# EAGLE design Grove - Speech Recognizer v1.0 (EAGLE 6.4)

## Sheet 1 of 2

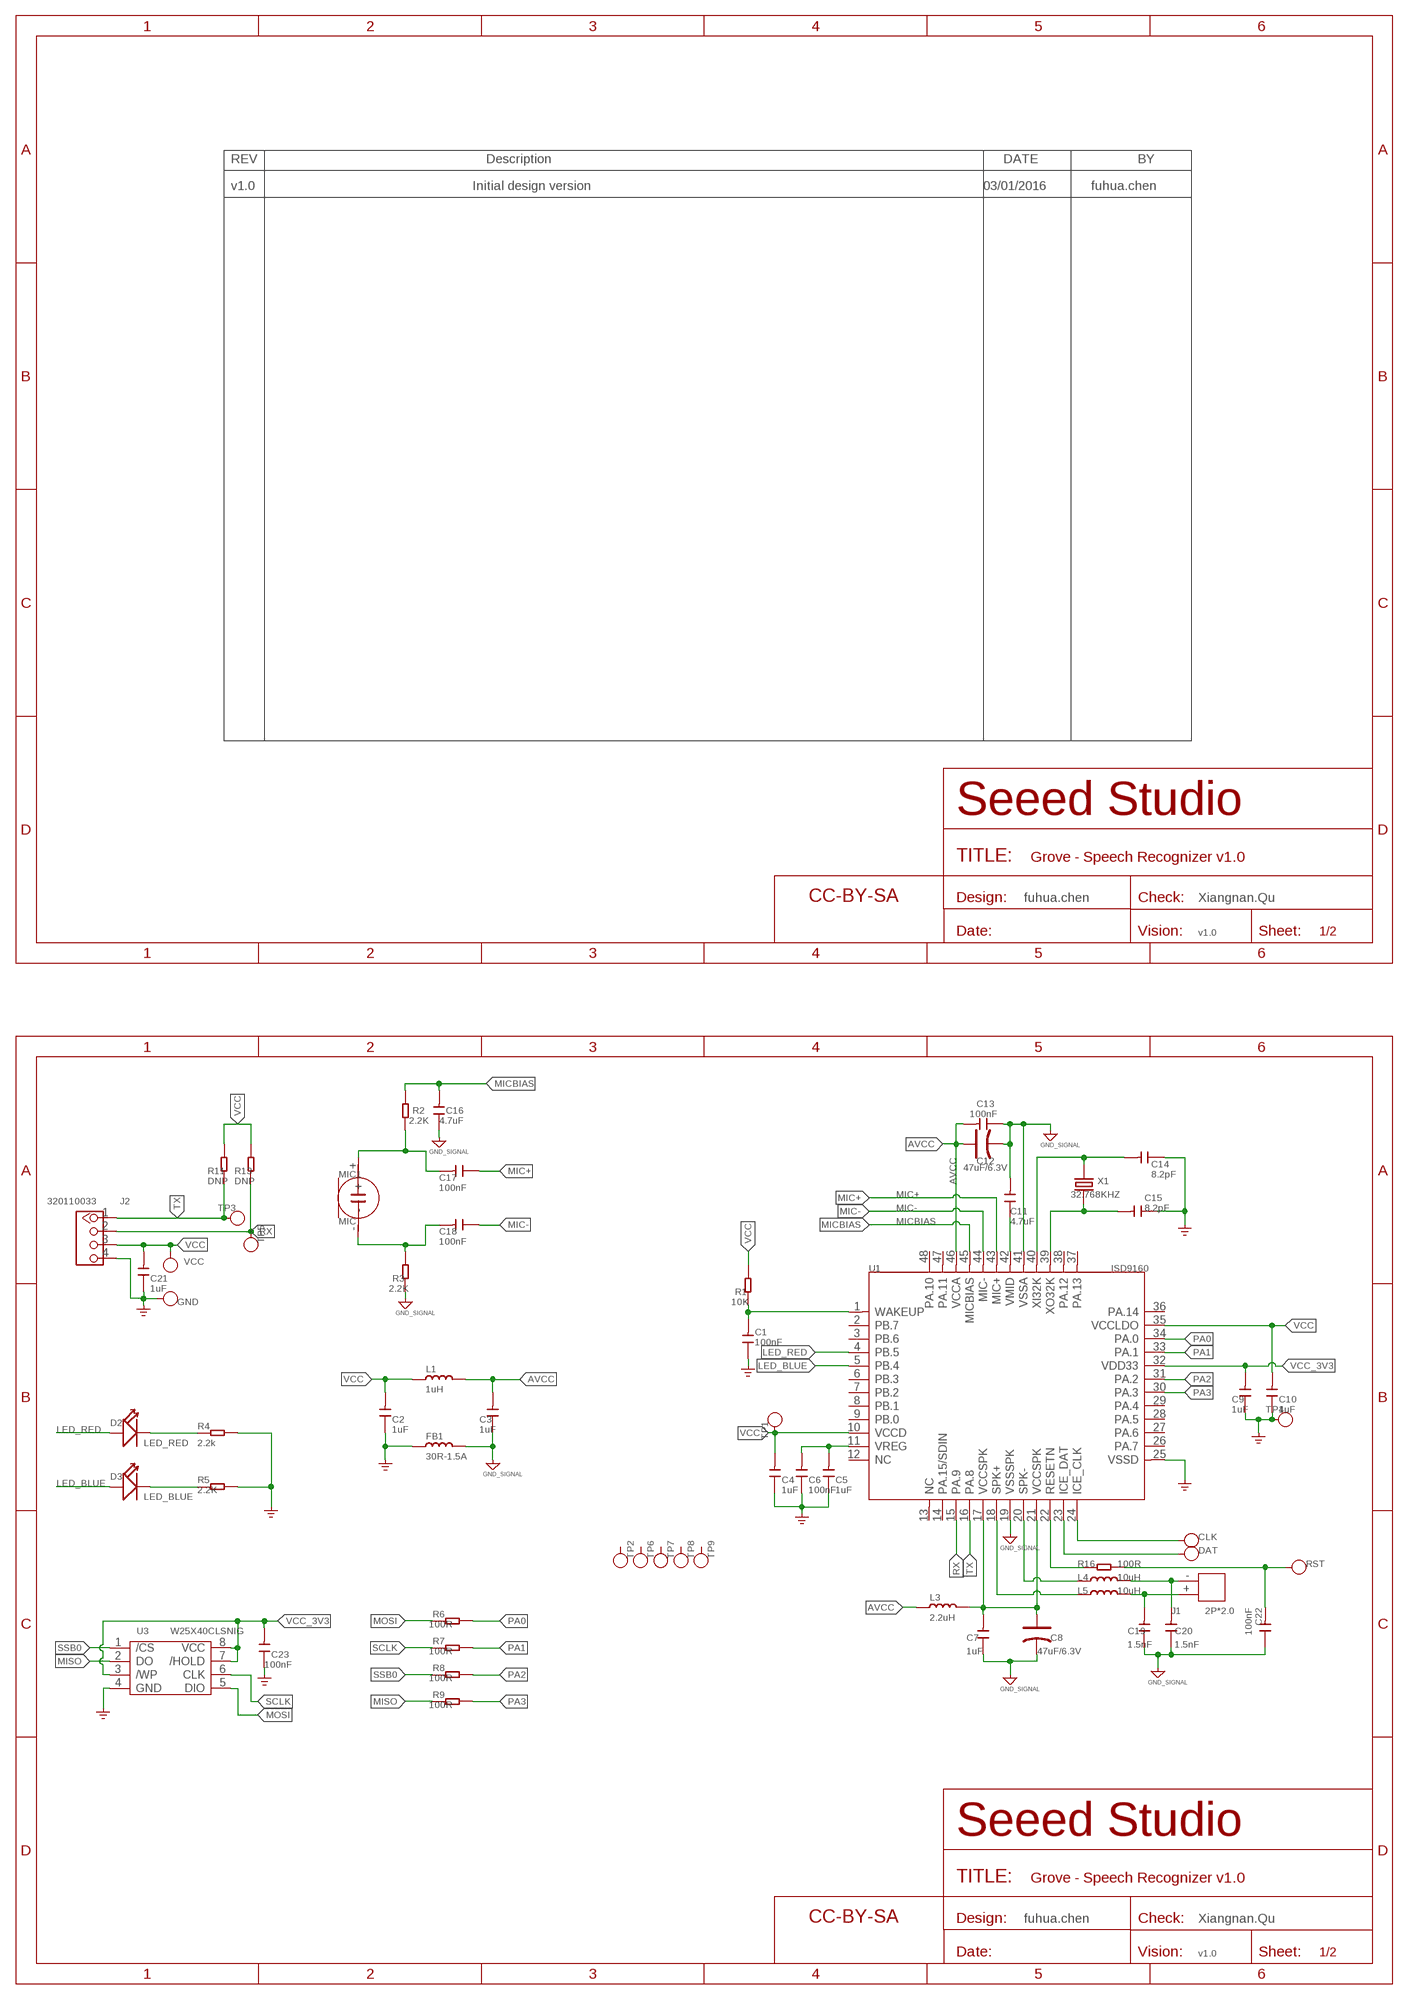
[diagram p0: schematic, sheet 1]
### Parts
C1  100nF  CAP-0402  [C0402]
C2  1uF  CAP-0402  [C0402]
C3  1uF  CAP-0402  [C0402]
C4  1uF  CAP-0402  [C0402]
C5  1uF  CAP-0402  [C0402]
C6  100nF  CAP-0402  [C0402]
C7  1uF  CAP-0402  [C0402]
C8  47uF/6.3V  CAP-POLAR-AVX-A  [AVX-A]
C9  1uF  CAP-0402  [C0402]
C10  1uF  CAP-0402  [C0402]
C11  4.7uF  CAP-0805  [C0805]
C12  47uF/6.3V  CAP-POLAR-AVX-A  [AVX-A]
C13  100nF  CAP-0402  [C0402]
C14  8.2pF  CAP-0402  [C0402]
C15  8.2pF  CAP-0402  [C0402]
C16  4.7uF  CAP-0805  [C0805]
C17  100nF  CAP-0402  [C0402]
C18  100nF  CAP-0402  [C0402]
C19  1.5nF  CAP-0402  [C0402]
C20  1.5nF  CAP-0402  [C0402]
C21  1uF  CAP-0402  [C0402]
C22  100nF  CAP-0402  [C0402]
C23  100nF  CAP-0402  [C0402]
CLK  DNP  TEST-POINT'4545'  [TP-D45MIL]
D2  LED_RED  LED-0402  [LED-0402]
D3  LED_BLUE  LED-0402  [LED-0402]
DAT  DNP  TEST-POINT'4545'  [TP-D45MIL]
FB1  30R-1.5A  INDUCTOR/FERRITE-BEAD'0603'  [L0603]
FR1  DNP  SEEEDSTUDIO-OPEN-SCH-FRAME  [SEEEDSTUDIO-PCB-FRAME]
FR2  DNP  SEEEDSTUDIO-OPEN-SCH-FRAME  [SEEEDSTUDIO-PCB-FRAME]
GND  DNP  TEST-POINT'4545'  [TP-D45MIL]
J1  2P*2.0  JST-2P-DIP'2.0'  [H2-2.0-6X4.5MM]
J2  320110033  GROVE-CONNECTOR-DIP-2.0  [HW4-2.0]
L1  1uH  INDUCTOR/FERRITE-BEAD'0805'  [L0805]
L3  2.2uH  INDUCTOR/FERRITE-BEAD'0805'  [L0805]
L4  10uH  INDUCTOR/FERRITE-BEAD'0805'  [L0805]
L5  10uH  INDUCTOR/FERRITE-BEAD'0805'  [L0805]
MIC1  MIC  MIC-2P'EAO-9745-PFA-C1033-28-008'  [MIC2-D9.7XH4.5MM]
R1  10K  RES-0402  [R0402]
R2  2.2K  RES-0402  [R0402]
R3  2.2K  RES-0402  [R0402]
R4  2.2k  RES-0402  [R0402]
R5  2.2K  RES-0402  [R0402]
R6  100R  RES-0402  [R0402]
R7  100R  RES-0402  [R0402]
R8  100R  RES-0402  [R0402]
R9  100R  RES-0402  [R0402]
R11  DNP  RES-0402  [R0402]
R13  DNP  RES-0402  [R0402]
R16  100R  RES-0402  [R0402]
RST  DNP  TEST-POINT'4545'  [TP-D45MIL]
TP1  TEST-POINT'4545'  [TP-D45MIL]
TP2  TEST-POINT'4545'  [TP-D45MIL]
TP3  TEST-POINT'4545'  [TP-D45MIL]
TP4  TEST-POINT'4545'  [TP-D45MIL]
TP5  TEST-POINT'4545'  [TP-D45MIL]
TP6  TEST-POINT'4545'  [TP-D45MIL]
TP7  TEST-POINT'4545'  [TP-D45MIL]
TP8  TEST-POINT'4545'  [TP-D45MIL]
TP9  TEST-POINT'4545'  [TP-D45MIL]
U1  ISD9160  MCU-ISD9160  [LQFP48-0.5-7X7MM]
U3  W25X40CLSNIG  FLASH-W25X80  [SOIC8-1.27-5.3X5.3MM]
VCC  DNP  TEST-POINT'4545'  [TP-D45MIL]
X1  32.768KHZ  CRYSTAL-2P-3215  [X2-SMD-3.2X1.5X0.55MM]

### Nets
AGND: C3.1 C7.1 C8.- C11.2 C12.- C13.1 C16.1 C19.1 C20.1 C22.1 FB1.2 R3.1 U1.19(VSSSPK) U1.41(VSSA) ; supply symbol labelled GND_SIGNAL
AVCC: C3.2 C12.+ C13.2 L1.2 L3.1 U1.46(VCCA)
GND: C1.1 C2.1 C4.1 C5.1 C6.1 C9.1 C10.1 C14.1 C15.1 C21.1 C23.1 FB1.1 GND.T J2.4 R4.1 R5.1 TP4.T U1.25(VSSD) U3.4(GND) ; supply symbol labelled GND_POWER
ICE_CLK: CLK.T U1.24(ICE_CLK)
LED_BLUE: D3.+ U1.5(PB.4)
LED_RED: D2.+ U1.4(PB.5)
MIC+: C17.1 U1.43(MIC+)
MIC-: C18.1 U1.44(MIC-)
MICBIAS: C16.2 R2.2 U1.45(MICBIAS)
MISO: R9.2 U3.2(DO)
MOSI: R6.2 U3.5(DIO)
N$1: C1.2 R1.1 U1.1(WAKEUP)
N$2: C7.2 C8.+ L3.2 U1.17(VCCSPK) U1.21(VCCSPK)
N$3: C5.2 C6.2 U1.11(VREG)
N$4: C11.1 U1.42(VMID)
N$5: C17.2 MIC1.+ R2.1
N$6: D2.- R4.2
N$7: C14.2 U1.40(XI32K) X1.1
N$8: C15.2 U1.39(XO32K) X1.2
N$9: C18.2 MIC1.- R3.2
N$10: D3.- R5.2
N$12: DAT.T U1.23(ICE_DAT)
N$13: L4.1 U1.20(SPK-)
N$15: C22.2 R16.1 RST.T
N$16: R16.2 U1.22(RESETN)
N$23: L5.1 U1.18(SPK+)
N$24: C20.2 J1.- L4.2
N$25: C19.2 J1.+ L5.2
PA0: R6.1 U1.34(PA.0)
PA1: R7.1 U1.33(PA.1)
PA2: R8.1 U1.31(PA.2)
PA3: R9.1 U1.30(PA.3)
RX: J2.2 R13.1 TP5.T U1.15(PA.9)
SCLK: R7.2 U3.6(CLK)
SSB0: R8.2 U3.1(/CS)
TX: J2.1 R11.1 TP3.T U1.16(PA.8)
VCC: C2.2 C4.2 C10.2 C21.2 J2.3 L1.1 R1.2 R11.2 R13.2 TP1.T U1.10(VCCD) U1.35(VCCLDO) VCC.T
VCC_3V3: C9.2 C23.2 U1.32(VDD33) U3.3(/WP) U3.7(/HOLD) U3.8(VCC)
Unconnected: TP2.T TP6.T TP7.T TP8.T TP9.T U1.2(PB.7) U1.3(PB.6) U1.6(PB.3) U1.7(PB.2) U1.8(PB.1) U1.9(PB.0) U1.12(NC) U1.13(NC) U1.14(PA.15/SDIN) U1.26(PA.7) U1.27(PA.6) U1.28(PA.5) U1.29(PA.4) U1.36(PA.14) U1.37(PA.13) U1.38(PA.12) U1.47(PA.11) U1.48(PA.10)

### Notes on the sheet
- v1.0 | Initial design version | 03/01/2016 | fuhua.chen
- fuhua.chen | Xiangnan.Qu
- v1.0
- fuhua.chen | Xiangnan.Qu
- v1.0

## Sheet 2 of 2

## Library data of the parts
C1-C7 C9-C11 C13-C23 = Discrete-new:CAP: Ceramic Capacitors
C8 C12 = Discrete-new:CAP-POLAR: Electrolytic Capacitors,Tantalum Capacitors and Super Capacitors
CLK DAT GND RST TP1-TP9 VCC = Discrete-new:TEST-POINT; PARTNO: DNP
D2 D3 = Discrete-new:LED
FB1 L1 L3-L5 = Discrete-new:INDUCTOR/FERRITE-BEAD
FR1 FR2 = moudle-new:SEEEDSTUDIO-OPEN-SCH-FRAME
J1 = Connector-new:JST-2P-DIP: 2P-2.0:320110049;2P-2.0-90D:320110027;2P-2.54:320110053;2P-2.54-90D:320110000
J2 = Connector-new:GROVE-CONNECTOR-DIP: 4P-2.0:320110033;4P-2.0-90D:320110034
MIC1 = Discrete-new:MIC-2P: 312030029
R1-R9 R11 R13 R16 = Discrete-new:RES
U1 = template:MCU-ISD9160
U3 = IC-new:FLASH-W25X80: 1M-BIT,2M-BIT,4M-BIT AND 8M-BIT SERIAL FLASH MEMORY WITH 4KB SECTORS AND DUAL OUTPUT SPI
X1 = Discrete-new:CRYSTAL-2P

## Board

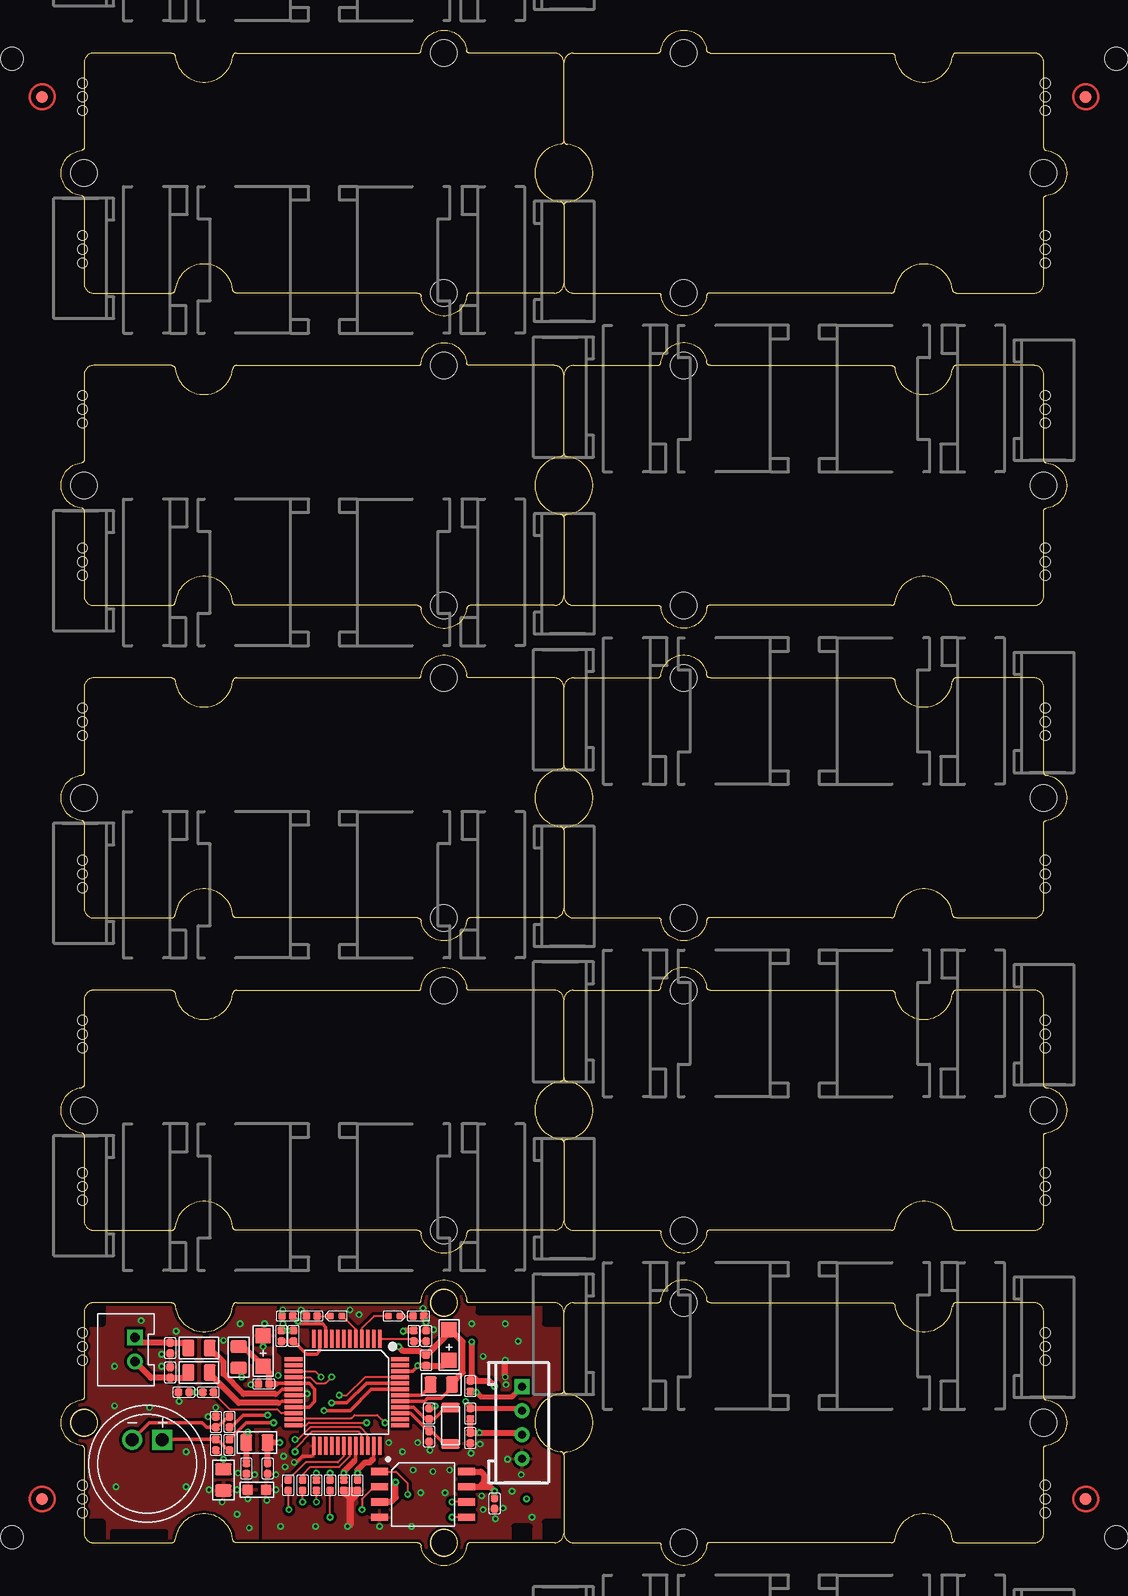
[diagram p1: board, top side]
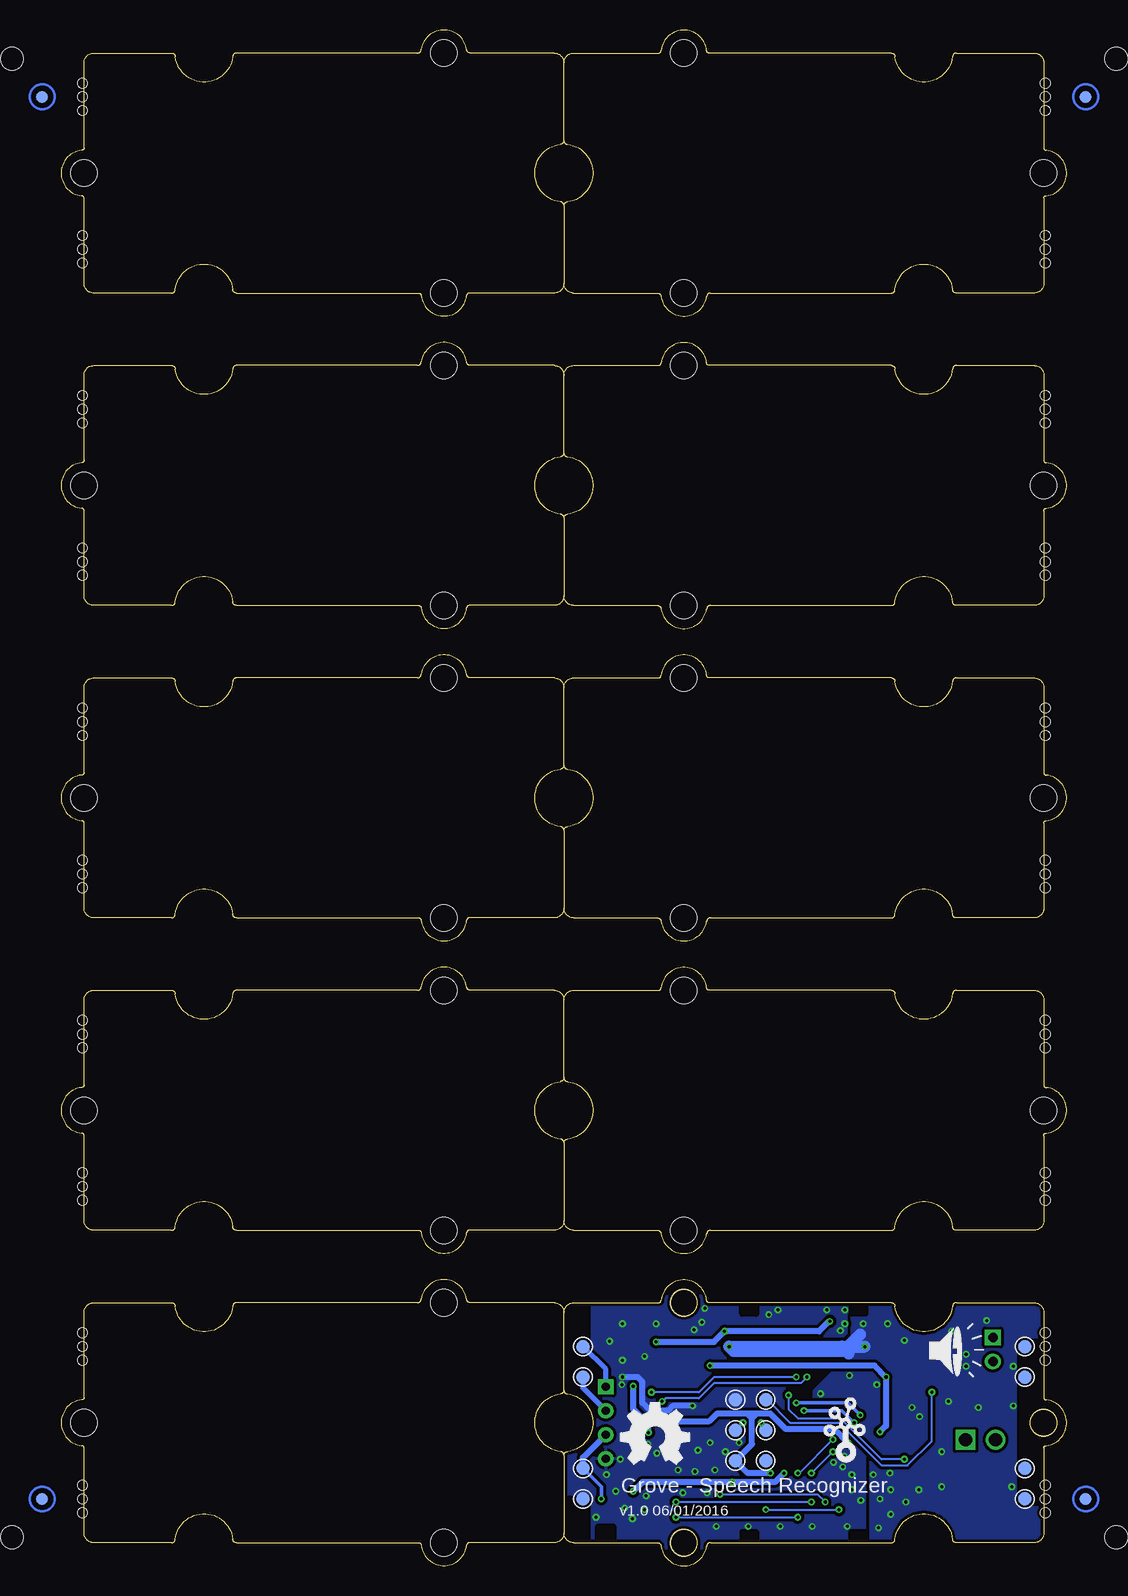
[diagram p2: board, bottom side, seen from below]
Size 83.82 x 127.98 mm. Coordinates in mm from the lower left corner, seen from the top.
Copper layers (1*16): Top 0.035mm / dielectric 1.5mm / Bottom 0.035mm
Design rules "SeeedStudio_2layer_DRU_no_angle_20140221 *": minimum track width 6mil, minimum drill 10mil, track to track 6mil, track to pad 6mil, pad to pad 6mil, via to via 6mil, smd to smd 0mil, copper to edge 10mil, drill to drill 10mil, minimum pad ring 10mil, minimum via ring 6mil, stop-mask expansion 2mil, vias tented up to drill 25mil, thermal gap 10mil
Holes 0.8 mm at 82.04,4.43 82.04,6.71 82.04,5.57 82.04,17.13 82.04,19.41 82.04,18.27 82.04,30.46 82.04,32.75 82.04,31.61 82.04,43.16 82.04,45.45 82.04,44.31 82.04,56.5 82.04,58.78 82.04,57.64 82.04,69.2 82.04,71.48 82.04,70.34 82.04,82.53 82.04,84.82 82.04,83.68 82.04,95.23 82.04,97.52 82.04,96.38 82.04,108.57 82.04,110.85 82.04,109.71 82.04,121.27 82.04,123.55 82.04,122.41 1.78,6.71 1.78,4.43 1.78,5.57 1.78,19.41 1.78,17.13 1.78,18.27 1.78,32.75 1.78,30.46 1.78,31.61 1.78,45.45 1.78,43.16 1.78,44.31 1.78,58.78 1.78,56.5 1.78,57.64 1.78,71.48 1.78,69.2 1.78,70.34 1.78,84.82 1.78,82.53 1.78,83.68 1.78,97.52 1.78,95.23 1.78,96.38 1.78,110.85 1.78,108.57 1.78,109.71 1.78,123.55 1.78,121.27 1.78,122.41
Holes 1.91 mm at 87.95,125.59 -4.13,125.59 -4.13,2.4 87.95,2.4
tRestrict: area 37.8,2 to 39.1,3.3
bRestrict: area 37.8,2 to 39.1,3.3

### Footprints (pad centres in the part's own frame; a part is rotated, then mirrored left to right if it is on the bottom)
C0402 = smd 0.635 x 0.635: 1 0,0.445; 2 0,-0.445
AVX-A = smd 1.27 x 1.27: + -1.27,0; - 1.27,0
C0805 = smd 1.397 x 1.016: 1 0,0.889; 2 0,-0.889
TP-D45MIL = smd 1.143 x 1.143: T 0,0
LED-0402 = smd 0.58 x 0.58: + -0.468,0; - 0.468,0
L0603 = smd 0.889 x 0.889: 1 -0.762,0; 2 0.762,0
H2-2.0-6X4.5MM = drill 0.8 pad 1.3 square: + -1,0.75 | drill 0.8 pad 1.3: - 1,0.75
HW4-2.0 = drill 0.7 pad 1.27 square: 1 -3,0 | drill 0.7 pad 1.27: 2 -1,0; 3 1,0; 4 3,0
L0805 = smd 1.016 x 1.397: 1 -0.889,0; 2 0.889,0
MIC2-D9.7XH4.5MM = drill 1.1 square: + 1.25,2 | drill 1.1: - -1.25,2
ROUND-MARK-1.0 = smd 1.016 x 1.016: P$1 0,0
R0402 = smd 0.635 x 0.635: 1 0,0.445; 2 0,-0.445
LQFP48-0.5-7X7MM = smd 1.5 x 0.3: 1 -4.45,2.75; 2 -4.45,2.25; 3 -4.45,1.75; 4 -4.45,1.25; 5 -4.45,0.75; 6 -4.45,0.25; 7 -4.45,-0.25; 8 -4.45,-0.75; 9 -4.45,-1.25; 10 -4.45,-1.75; 11 -4.45,-2.25; 12 -4.45,-2.75; 25 4.45,-2.75; 26 4.45,-2.25; 27 4.45,-1.75; 28 4.45,-1.25; 29 4.45,-0.75; 30 4.45,-0.25; 31 4.45,0.25; 32 4.45,0.75; 33 4.45,1.25; 34 4.45,1.75; 35 4.45,2.25; 36 4.45,2.75 | smd 0.3 x 1.5: 13 -2.75,-4.45; 14 -2.25,-4.45; 15 -1.75,-4.45; 16 -1.25,-4.45; 17 -0.75,-4.45; 18 -0.25,-4.45; 19 0.25,-4.45; 20 0.75,-4.45; 21 1.25,-4.45; 22 1.75,-4.45; 23 2.25,-4.45; 24 2.75,-4.45; 37 2.75,4.45; 38 2.25,4.45; 39 1.75,4.45; 40 1.25,4.45; 41 0.75,4.45; 42 0.25,4.45; 43 -0.25,4.45; 44 -0.75,4.45; 45 -1.25,4.45; 46 -1.75,4.45; 47 -2.25,4.45; 48 -2.75,4.45
SOIC8-1.27-5.3X5.3MM = smd 0.62 x 1.4: 1 -1.905,-3.623; 2 -0.635,-3.623; 3 0.635,-3.623; 4 1.905,-3.623; 5 1.905,3.623; 6 0.635,3.623; 7 -0.635,3.623; 8 -1.905,3.623
GROVE-TEST-PLATFORM = hole 2.2: -10,-10; -10,10; 20,0
GROVE-1*2-TEST-PLATFORM = hole 2.2: 10.635,10; 10.635,-10; -19.365,0
X2-SMD-3.2X1.5X0.55MM = smd 0.762 x 1.524: 1 -1.524,0; 2 1.524,0

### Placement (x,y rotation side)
C1  30.42,19.16 0 top
C2  17.21,8.11 180 top
C3  15.43,8.11 180 top
C4  18.86,20.81 90 top
C5  18.35,19.16 0 top
C6  19.37,19.16 0 top
C7  16.89,15.16 90 top
C8  16.83,17.89 90 top
C9  23.56,6.71 180 top
C10  24.7,6.71 180 top
C11  31.69,15.1 90 top
C12  32.32,18.4 90 top
C13  30.42,17.13 0 top
C14  30.67,12.68 0 top
C15  30.67,10.78 180 top
C16  13.53,7.16 180 top
C17  14.03,10.08 0 top
C18  14.03,11.98 180 top
C19  9.08,18.14 180 top
C20  9.08,16.11 0 top
C21  34.1,10.65 180 top
C22  10.22,14.46 90 top
C23  36.13,5.19 180 top
CLK  25.08,11.29 0 bottom
D2  27.75,20.81 0 top
D3  22.92,20.81 180 top
DAT  27.62,11.29 0 bottom
FB1  16.32,6.33 180 top
FR1  not placed on the board
FR2  not placed on the board
GND  40.32,5.57 0 bottom
J1  5.4,18.02 270 top
J2  38.42,11.92 270 top
L1  16.32,10.27 180 top
L3  14.8,17.38 90 top
L4  11.49,16.11 180 top
L5  11.49,18.14 180 top
MIC1  7.18,8.49 0 top
P1  [ROUND-MARK-1.0]  85.41,122.41 180 top
P2  [ROUND-MARK-1.0]  -1.59,122.41 180 top
P3  [ROUND-MARK-1.0]  85.41,5.57 180 top
P4  [ROUND-MARK-1.0]  -1.59,5.57 180 top
P5  [ROUND-MARK-1.0]  85.41,122.41 180 bottom
P6  [ROUND-MARK-1.0]  -1.59,122.41 180 bottom
P7  [ROUND-MARK-1.0]  -1.59,5.57 180 bottom
P8  [ROUND-MARK-1.0]  85.41,5.57 180 bottom
R1  29.4,19.16 180 top
R2  12.89,10.08 0 top
R3  12.89,11.98 0 top
R4  29.78,20.81 270 top
R5  20.89,20.81 90 top
R6  22.42,6.71 0 top
R7  21.27,6.71 0 top
R8  20.13,6.71 0 top
R9  18.92,6.71 0 top
R11  34.1,14.97 180 top
R13  34.1,12.68 0 top
R16  12.26,14.46 90 top
RST  25.08,13.83 0 bottom
TP1  27.62,8.75 0 bottom
TP2  25.08,8.75 0 bottom
TP3  40.32,18.27 0 bottom
TP4  27.62,13.83 0 bottom
TP5  40.32,15.73 0 bottom
TP6  3.49,18.27 0 bottom
TP7  3.49,15.73 0 bottom
TP8  3.49,8.11 0 bottom
TP9  3.49,5.57 0 bottom
U1  23.81,14.46 270 top
U3  30.16,5.95 270 top
U4  [GROVE-TEST-PLATFORM]  21.91,90.03 180 top
U5  [GROVE-TEST-PLATFORM]  61.91,90.03 0 top
U6  [GROVE-TEST-PLATFORM]  21.91,63.99 180 top
U7  [GROVE-TEST-PLATFORM]  61.91,63.99 0 top
U8  [GROVE-TEST-PLATFORM]  21.91,37.96 180 top
U9  [GROVE-TEST-PLATFORM]  61.91,37.96 0 top
U10  [GROVE-TEST-PLATFORM]  61.91,11.92 0 top
U12  [GROVE-TEST-PLATFORM]  21.91,116.06 180 top
U13  [GROVE-TEST-PLATFORM]  61.91,116.06 0 top
U$15  [OSHW_FILLX200_NOTEXT]  37.15,8.49 0 bottom
U$18  [GROVE-1*2-TEST-PLATFORM]  21.27,11.92 0 top
U$20  [TWIGLOGO_SMALL]  20.64,8.49 0 bottom
VCC  40.32,8.11 0 bottom
X1  32.45,11.67 270 top

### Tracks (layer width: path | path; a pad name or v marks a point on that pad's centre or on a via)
AGND  (via drill 0.25 pad 0.51)
  Top 0.305: U1.41 30.3,13.71 30.54,13.95 31.69,13.95 32.58,14.84 C11.2 | C22.1 9.78,13.76 v9.84,13.7 | U1.19 20.39,14.21 v20.51,14.33
  Top 0.508: 32.32,19.41 30.48,17.57 C13.1 30.23,17.57 29.91,17.89 28.51,17.89 v28.13,18.27 | C12.- 32.32,19.41 | C11.2 32.58,15.22 33.47,16.11 33.47,18.65 32.7,19.41 32.32,19.41
  Bottom 1.016: 18.73,18.27 v28.13,18.27 27.75,17.89 18.35,17.89 | 18.23,18.27 v16.83,18.27 | 18.73,18.27 18.35,17.89 | 18.35,17.89 18.16,17.7 | 18.73,18.27 18.23,18.27 | 18.23,18.27 17.21,19.29
  other vias: 12.26,12.43 16.96,20.18 14.92,20.18 12.89,13.19 8.38,16.62 8.38,17.64 14.67,6.33 15.56,5.57 13.4,5.32 15.81,15.1 18.1,15.86 15.69,3.16 14.67,4.3 13.53,18.78 9.59,19.54 6.67,20.43 4.45,16.62 4.45,13.32 7.37,13.19 12.32,6.33 14.73,7.73 16.13,7.6 10.41,6.59 4.57,6.59 10.41,9.51
  pour Top (isolate 0.254, rank 3): 1.59,22.46 17.84,22.46 17.84,17.76 21.02,14.59 21.02,11.79 20,10.78 17.84,10.78 16.32,9.25 16.32,1.51 1.59,1.51
  pour Bottom (isolate 0.254, rank 3): 1.59,22.46 17.84,22.46 17.84,17.76 21.02,14.59 21.02,11.79 20,10.78 17.84,10.78 16.32,9.25 16.32,1.51 1.59,1.51
AVCC  (via drill 0.25 pad 0.51)
  Top 0.305: U1.46 29.31,16.21 29.78,16.68
  Top 0.508: C3.2 L1.2 15.43,11.03 v15.56,11.16 | C12.+ 31.88,16.68 C13.2 29.78,16.68 v29.72,16.68 | v15.05,15.73 15.05,16.24 L3.1
  Bottom 0.508: v15.56,11.16 15.05,11.67 v15.05,15.73 16,16.68 v29.72,16.68
GND  (via drill 0.25 pad 0.51)
  Top 0.305: C14.1 30.99,13.13 v31.18,13.32 | 21.06,9.43 U1.25 21.06,9.3 20.89,9.13 20.13,9.13 19.62,8.62 v19.43,8.62 | C4.1 18.42,21.26 v18.48,21.32 | R5.1 20.45,20.87 v20,21.32 | R4.1 30.23,20.49 v30.42,20.3
  Top 0.508: v37.02,15.73 v37.02,17.13
  Top 0.61: C9.1 C10.1 24.7,6.08 24.07,5.44 | 24.07,5.44 24.07,3.48 v23.88,3.29 | 24.07,5.7 24.07,6.21 | 24.07,5.44 24.07,5.7 | 24.07,5.7 23.56,6.21
  Bottom 0.508: v31.18,13.32 32.83,13.32 33.21,12.94 34.74,12.94 35.37,13.57 35.37,15.35 35.75,15.73 v37.02,15.73
  other vias: 31.05,19.67 30.73,9.64 34.16,9.38 17.15,5.44 17.91,7.6 34.93,10.14 37.21,8.87 38.35,7.6 36.83,4.81 36.2,3.92 35.18,4.68 26.54,3.29 21.21,3.29 18.29,3.29 17.91,6.33 18.54,9.13 29.72,10.27 27.31,10.27 29.34,7.98 32.39,7.98 37.08,15.1 29.21,3.29 29.97,6.08 32,6.08 35.05,5.83 37.59,6.21 39.24,4.05 28.45,9.51 18.67,8.24 30.99,7.86 18.48,20.18 18.86,19.6 34.23,20.18 37.02,20.18 35.18,17.45 38.1,18.72 24.83,20.94 24.07,21.32 30.16,21.45
  pour Top (isolate 0.254, rank 6): 1.59,22.46 42.23,22.46 42.23,1.51 1.59,1.51
  pour Bottom (isolate 0.254, rank 6): 1.59,22.46 42.23,22.46 42.23,1.51 1.59,1.51
ICE_CLK  (via drill 0.25 pad 0.51)
  Top 0.152: U1.24 20.43,11.71 20.64,11.92 v25.46,11.92
  Bottom 0.152: CLK.T 25.08,11.54 v25.46,11.92
LED_BLUE
  Top 0.152: U1.5 24.56,19.73 23.48,20.81 D3.+
LED_RED
  Top 0.152: D2.+ 26.07,20.81 25.06,19.8 U1.4
MIC+  (via drill 0.25 pad 0.51)
  Top 0.305: C17.1 14.03,10.65 14.16,10.65 15.43,11.92 v17.72,11.92 | U1.43 25.84,14.71 24.07,12.94 v21.91,12.94
  Bottom 0.305: v21.91,12.94 18.73,12.94 v17.72,11.92
MIC-  (via drill 0.25 pad 0.51)
  Top 0.305: v17.21,12.56 15.18,12.56 14.16,11.54 C18.1 | U1.44 25.45,15.21 23.81,13.57 v22.54,13.57
  Bottom 0.305: v22.54,13.57 18.23,13.57 v17.21,12.56
MICBIAS  (via drill 0.25 pad 0.51)
  Top 0.152: U1.45 25.32,15.71 23.81,14.21 v23.18,14.21 | C16.2 v13.53,8.87 13.53,9 R2.2
  Bottom 0.152: v23.18,14.21 23.18,13.06 22.42,12.3 18.86,12.3 15.43,8.87 v13.53,8.87
MISO  (via drill 0.25 pad 0.51)
  Top 0.152: U3.2 26.1,6.59 25.08,5.57 v25.08,4.68 | R9.2 18.92,4.75 v18.99,4.68
  Bottom 0.152: v25.08,4.68 19.11,4.68 v18.99,4.68
MOSI  (via drill 0.25 pad 0.51)
  Top 0.152: U3.5 v32.58,4.05 | v22.42,4.05 R6.2
  Bottom 0.152: v32.58,4.05 v22.42,4.05
N$1
  Top 0.152: C1.2 R1.1 29.21,18.91 U1.1
N$2
  Top 0.305: 17.91,15.16 17.96,15.21 U1.17 20.65,15.21 21.15,14.72 21.15,13.7 20.66,13.21 U1.21
  Top 0.508: L3.2 15.18,18.27 C8.+ 17.34,16.11 C7.2 17.91,15.16
N$3
  Top 0.305: U1.11 21.56,17.93 21.27,17.64 20.45,17.64 C6.2 C5.2
N$4
  Top 0.305: U1.42 30.04,14.21 30.8,14.97 C11.1
N$5
  Top 0.305: C17.2 13.91,9.64 13.02,10.52 R2.1 8.46,10.52 MIC1.+
N$6
  Top 0.152: D2.- R4.2
N$7
  Top 0.305: U1.40 29.38,13.21 30.35,12.24 C14.2 31.12,12.24 31.75,12.87 31.81,12.94 32.07,13.19 X1.1
N$8
  Top 0.305: U1.39 29.12,12.71 30.61,11.22 C15.2 30.86,11.22 31.94,10.14 X1.2
N$9
  Top 0.305: C18.2 13.91,12.43 13.02,11.54 R3.2 12.13,11.54 11.75,11.92 7.36,11.92 MIC1.-
N$10
  Top 0.152: R5.2 D3.-
N$12  (via drill 0.25 pad 0.51)
  Top 0.152: U1.23 20.29,12.21 20.38,12.3 24.19,12.3 24.45,12.56 26.35,12.56 v26.99,11.92
  Bottom 0.152: DAT.T 27.62,11.54 27.37,11.54 v26.99,11.92
N$13
  Top 0.305: U1.20 18.36,13.71 18.23,13.57 18.1,13.57
  Top 0.508: 18.1,13.57 14.8,13.57 12.38,15.99 L4.1
N$15  (via drill 0.25 pad 0.51)
  Top 0.152: R16.1 v11.24,14.46 C22.2
  Bottom 0.152: RST.T 24.96,13.83 23.05,11.92 18.99,11.92 15.43,8.37 13.27,8.37 11.24,10.4 v11.24,14.46
N$16
  Top 0.152: R16.2 12.76,14.46 12.76,14.33 14.03,13.06 18,13.06 18.35,12.71 U1.22
N$23
  Top 0.305: U1.18 18.41,14.71 18.04,14.33 17.84,14.33
  Top 0.508: L5.1 13.53,17 13.53,15.99 15.18,14.33 17.84,14.33
N$24
  Top 0.508: L4.2 10.16,15.67 C20.2 7.5,15.67 J1.-
N$25
  Top 0.508: L5.2 10.16,18.59 C19.2 6.58,18.59 J1.+
PA0  (via drill 0.25 pad 0.51)
  Top 0.152: R6.1 v22.42,7.73 | v19.5,10.52 19.75,10.52 20.77,11.54 24.96,11.54 25.56,10.93 U1.34
  Bottom 0.152: v22.42,7.73 22.29,7.73 v19.5,10.52
PA1  (via drill 0.25 pad 0.51)
  Top 0.152: R7.1 v21.27,7.73 | U1.33 25.06,10.93 24.83,11.16 20.89,11.16 19.5,9.76 v19.5,9.51
  Bottom 0.152: v19.5,9.51 v21.27,7.73
PA2
  Top 0.152: U1.31 24.06,9.12 23.18,8.24 20.77,8.24 20.13,7.6 R8.1
PA3
  Top 0.152: U1.30 23.56,9.13 23.05,8.62 20.38,8.62 R9.1
RX  (via drill 0.25 pad 0.51)
  Top 0.152: v33.72,13.7 33.72,13.51 R13.1 | U1.15 21.17,16.21 v21.65,15.73
  Top 0.406: R13.1 38.21,13.13 J2.2
  Bottom 0.152: v33.72,13.7 33.47,13.95 30.67,13.95 29.4,15.22 22.16,15.22 v21.65,15.73
  Bottom 0.406: TP5.T 40.32,14.83 J2.2
SCLK  (via drill 0.25 pad 0.51)
  Top 0.152: U3.6 v32.58,5.32 | v21.27,5.32 R7.2
  Bottom 0.152: v32.58,5.32 v21.27,5.32
SSB0  (via drill 0.25 pad 0.51)
  Top 0.152: U3.1 27.9,7.86 28.89,6.87 v28.89,5.95 | v20.13,5.32 R8.2
  Bottom 0.152: v28.89,5.95 20.77,5.95 v20.13,5.32
TX  (via drill 0.25 pad 0.51)
  Top 0.152: U1.16 20.77,15.71 21.25,15.22 22.04,15.22 v22.54,15.73 | R11.1 34.55,14.53 v34.61,14.46
  Top 0.406: v34.61,14.46 34.99,14.08 37.58,14.08 J2.1
  Bottom 0.152: v34.61,14.46 30.67,14.46 29.4,15.73 v22.54,15.73
  Bottom 0.406: J2.1 38.42,16.37 TP3.T
VCC  (via drill 0.25 pad 0.51)
  Top 0.305: U1.35 26.06,8.96 25.91,8.81 | 38.86,5.51 v38.8,5.57 | U1.10 22.06,19.89 21.78,20.18 19.94,20.18 v19.75,20.37 C4.2 19.24,20.81
  Top 0.508: C2.2 L1.1 v18.23,10.27 | 25.97,8.87 25.91,8.81 25.72,8.62 25.34,8.62 24.7,7.98 v24.7,7.73 C10.2 | J2.3 38.24,11.1 v34.86,11.1 C21.2 R13.2 | 34.23,15.41 R11.2 34.04,15.41 | R1.2 28.58,19.6 v28.51,19.54 | v34.23,18.65 34.23,15.86 | 34.23,15.73 34.23,15.41 | 34.23,15.86 34.23,15.73 | 34.23,15.73 34.1,15.6 | 34.23,15.86 34.61,15.48 | 34.23,15.41 35.69,15.41 v36.13,14.97
  Bottom 0.305: v38.8,5.57 38.8,6.59 VCC.T
  Bottom 0.508: v34.23,18.65 29.4,18.65 v28.51,19.54 20.64,19.54 19.81,20.37 v19.75,20.37 | VCC.T 40.32,9.02 J2.3 | 35.12,12.05 34.86,12.05 | 34.86,12.05 34.61,12.05 | 35.12,12.05 36.13,13.06 v36.13,14.97 | 34.86,11.79 34.86,12.05 | v34.86,11.1 34.86,11.79 | 34.86,11.79 35.12,12.05 | 34.86,11.79 34.61,12.05 | v24.7,7.73 26.61,7.73 TP1.T 26.23,10.14 26.23,12.3 | v18.23,10.27 19.37,11.41 23.43,11.41 24.7,12.68 25.85,12.68 | 34.61,12.05 29.78,12.05 29.15,12.68 26.61,12.68 | 25.85,12.68 26.23,12.68 | 26.23,12.68 26.61,12.68 | 26.23,12.3 26.23,12.68 | 26.23,12.3 25.85,12.68 | 26.23,12.3 26.61,12.68
VCC_3V3  (via drill 0.25 pad 0.51)
  Top 0.305: U1.32 24.56,8.86 24.45,8.75
  Top 0.508: C9.2 v23.56,7.73 23.56,7.86 24.45,8.75 | U3.8 34.99,7.86 35.24,7.6 35.24,7.1 | 35.24,6.97 35.24,6.59 | C23.2 v36.13,6.21 35.75,6.59 | U3.7 34.86,6.59 | 34.86,6.59 35.24,6.59 | 35.24,6.59 35.75,6.59 | 35.24,7.1 35.75,6.59 | 35.24,7.1 35.24,6.97 | 35.24,6.97 34.86,6.59 | U3.3 27.5,5.32 27.88,5.7 v27.88,6.97
  Bottom 0.508: v23.56,7.73 24.32,6.97 v27.88,6.97 28.26,6.97 35.37,6.97 v36.13,6.21

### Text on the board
bPlace: Grove - Speech Recognizer | v1.0 06/01/2016
bDocu: PLAY | REC | VCC | GND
